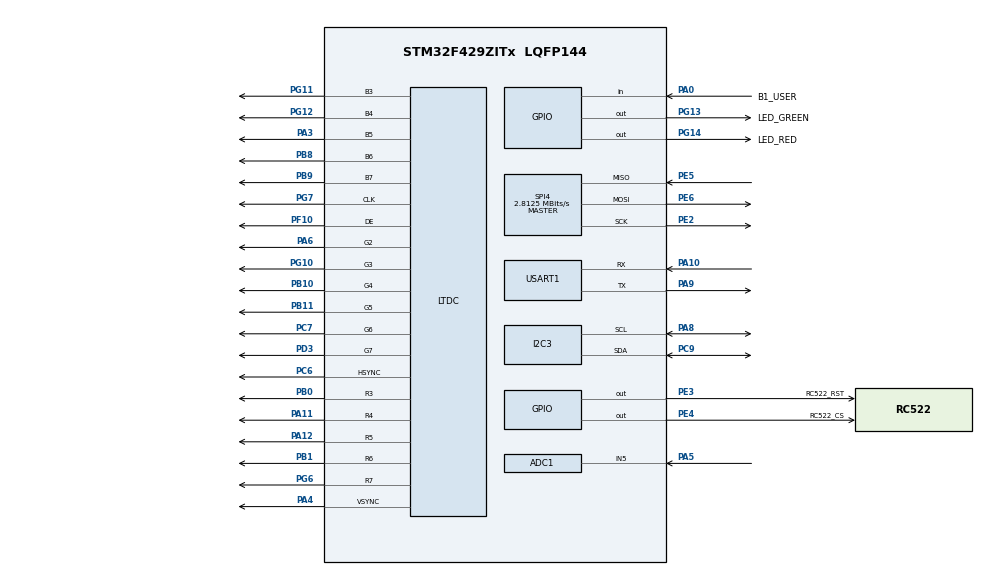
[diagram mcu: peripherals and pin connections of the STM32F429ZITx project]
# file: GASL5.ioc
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ADC1.Channel-0\#ChannelRegularConversion=ADC_CHANNEL_5
ADC1.ContinuousConvMode=ENABLE
ADC1.NbrOfConversionFlag=1
ADC1.Rank-0\#ChannelRegularConversion=1
ADC1.SamplingTime-0\#ChannelRegularConversion=ADC_SAMPLETIME_56CYCLES
ADC1.master=1
DMA2D.ColorMode=DMA2D_OUTPUT_RGB565
Dma.ADC1.0.Direction=DMA_PERIPH_TO_MEMORY
Dma.ADC1.0.FIFOMode=DMA_FIFOMODE_DISABLE
Dma.ADC1.0.Instance=DMA2_Stream0
Dma.ADC1.0.MemDataAlignment=DMA_MDATAALIGN_HALFWORD
Dma.ADC1.0.MemInc=DMA_MINC_ENABLE
Dma.ADC1.0.Mode=DMA_CIRCULAR
Dma.ADC1.0.PeriphDataAlignment=DMA_PDATAALIGN_HALFWORD
Dma.ADC1.0.PeriphInc=DMA_PINC_DISABLE
Dma.ADC1.0.Priority=DMA_PRIORITY_HIGH
Dma.Request0=ADC1
Dma.Request1=USART1_TX
Dma.USART1_TX.1.Direction=DMA_MEMORY_TO_PERIPH
Dma.USART1_TX.1.FIFOMode=DMA_FIFOMODE_DISABLE
Dma.USART1_TX.1.Instance=DMA2_Stream7
Dma.USART1_TX.1.MemDataAlignment=DMA_MDATAALIGN_BYTE
Dma.USART1_TX.1.MemInc=DMA_MINC_ENABLE
Dma.USART1_TX.1.Mode=DMA_NORMAL
Dma.USART1_TX.1.PeriphDataAlignment=DMA_PDATAALIGN_BYTE
Dma.USART1_TX.1.PeriphInc=DMA_PINC_DISABLE
Dma.USART1_TX.1.Priority=DMA_PRIORITY_LOW
LTDC.Alpha0_L0=0
LTDC.Alpha_L0=255
LTDC.BlendingFactor1_L0=LTDC_BLENDING_FACTOR1_PAxCA
LTDC.BlendingFactor2_L0=LTDC_BLENDING_FACTOR2_PAxCA
LTDC.ImageHeight_L0=320
LTDC.ImageWidth_L0=240
LTDC.Layers=0
LTDC.PixelFormat_L0=LTDC_PIXEL_FORMAT_RGB565
LTDC.WindowX1_L0=240
LTDC.WindowY1_L0=320
Mcu.Family=STM32F4
Mcu.Name=STM32F429ZITx
Mcu.Package=LQFP144
NVIC.DMA2_Stream0_IRQn=true\:0\:0\:false\:false\:true\:false\:true\:true
NVIC.DMA2_Stream7_IRQn=true\:0\:0\:false\:false\:true\:false\:true\:true
NVIC.PriorityGroup=NVIC_PRIORITYGROUP_4
NVIC.TIM6_DAC_IRQn=true\:15\:0\:false\:false\:true\:false\:true\:true
NVIC.TimeBase=TIM6_DAC_IRQn
NVIC.TimeBaseIP=TIM6
NVIC.USART1_IRQn=true\:0\:0\:false\:false\:true\:false\:true\:true
PA0/WKUP.GPIO_Label=B1_USER
PA0/WKUP.GPIO_PuPd=GPIO_PULLDOWN
PA0/WKUP.Signal=GPIO_Input
PA10.Mode=Asynchronous
PA10.Signal=USART1_RX
PA11.Mode=RGB565
PA11.Signal=LTDC_R4
PA12.Mode=RGB565
PA12.Signal=LTDC_R5
PA13.Mode=Serial_Wire
PA13.Signal=SYS_JTMS-SWDIO
PA14.Mode=Serial_Wire
PA14.Signal=SYS_JTCK-SWCLK
PA3.Mode=RGB565
PA3.Signal=LTDC_B5
PA4.Mode=RGB565
PA4.Signal=LTDC_VSYNC
PA5.Signal=ADCx_IN5
PA6.Mode=RGB565
PA6.Signal=LTDC_G2
PA8.Mode=I2C
PA8.Signal=I2C3_SCL
PA9.Mode=Asynchronous
PA9.Signal=USART1_TX
PB0.Mode=RGB565
PB0.Signal=LTDC_R3
PB1.Mode=RGB565
PB1.Signal=LTDC_R6
PB10.Mode=RGB565
PB10.Signal=LTDC_G4
PB11.Mode=RGB565
PB11.Signal=LTDC_G5
PB8.Mode=RGB565
PB8.Signal=LTDC_B6
PB9.Mode=RGB565
PB9.Signal=LTDC_B7
PC6.Mode=RGB565
PC6.Signal=LTDC_HSYNC
PC7.Mode=RGB565
PC7.Signal=LTDC_G6
PC9.Mode=I2C
PC9.Signal=I2C3_SDA
PD3.Mode=RGB565
PD3.Signal=LTDC_G7
PE2.Mode=Full_Duplex_Master
PE2.Signal=SPI4_SCK
PE3.GPIO_Label=RC522_RST
PE3.GPIO_PuPd=GPIO_NOPULL
PE3.GPIO_Speed=GPIO_SPEED_FREQ_HIGH
PE3.PinState=GPIO_PIN_SET
PE3.Signal=GPIO_Output
PE4.GPIO_Label=RC522_CS
PE4.PinState=GPIO_PIN_SET
PE4.Signal=GPIO_Output
PE5.Mode=Full_Duplex_Master
PE5.Signal=SPI4_MISO
PE6.Mode=Full_Duplex_Master
PE6.Signal=SPI4_MOSI
PF10.Mode=RGB565
PF10.Signal=LTDC_DE
PG13.GPIO_Label=LED_GREEN
PG13.Signal=GPIO_Output
PG14.GPIO_Label=LED_RED
PG14.Signal=GPIO_Output
PG10.Mode=RGB565
PG10.Signal=LTDC_G3
PG11.Mode=RGB565
PG11.Signal=LTDC_B3
PG12.Mode=RGB565
PG12.Signal=LTDC_B4
PG6.Mode=RGB565
PG6.Signal=LTDC_R7
PG7.Mode=RGB565
PG7.Signal=LTDC_CLK
PH0/OSC_IN.Mode=HSE-External-Oscillator
PH0/OSC_IN.Signal=RCC_OSC_IN
PH1/OSC_OUT.Mode=HSE-External-Oscillator
PH1/OSC_OUT.Signal=RCC_OSC_OUT
ProjectManager.HeapSize=0x200
ProjectManager.StackSize=0x400
ProjectManager.TargetToolchain=STM32CubeIDE
RCC.48MHZClocksFreq_Value=90000000
RCC.AHBFreq_Value=180000000
RCC.APB1CLKDivider=RCC_HCLK_DIV4
RCC.APB1Freq_Value=45000000
RCC.APB1TimFreq_Value=90000000
RCC.APB2CLKDivider=RCC_HCLK_DIV2
RCC.APB2Freq_Value=90000000
RCC.APB2TimFreq_Value=180000000
RCC.CortexFreq_Value=180000000
RCC.EnbaleCSS=true
RCC.HCLKFreq_Value=180000000
RCC.HSE_VALUE=25000000
RCC.HSI_VALUE=16000000
RCC.LSE_VALUE=32768
RCC.PLLM=25
RCC.PLLN=360
RCC.PLLSAIDivR=RCC_PLLSAIDIVR_8
RCC.PLLSAIN=192
RCC.PLLSAIR=4
RCC.PLLSourceVirtual=RCC_PLLSOURCE_HSE
RCC.PWREXT_OverDrive=PWREXT_OverDrive_ACTIVATED
RCC.PWR_Regulator_Voltage_Scale=PWR_REGULATOR_VOLTAGE_SCALE1
RCC.SYSCLKFreq_VALUE=180000000
RCC.SYSCLKSource=RCC_SYSCLKSOURCE_PLLCLK
RCC.VCOOutputFreq_Value=360000000
SH.ADCx_IN5.0=ADC1_IN5,IN5
SPI4.BaudRatePrescaler=SPI_BAUDRATEPRESCALER_32
SPI4.CalculateBaudRate=2.8125 MBits/s
SPI4.Direction=SPI_DIRECTION_2LINES
SPI4.Mode=SPI_MODE_MASTER
SPI4.VirtualType=VM_MASTER
STMicroelectronics.X-CUBE-TOUCHGFX.4.25.0.ApplicationCcGraphicsJjApplication=TouchGFXOoGenerator
STMicroelectronics.X-CUBE-TOUCHGFX.4.25.0.tgfx_custom_height=320
STMicroelectronics.X-CUBE-TOUCHGFX.4.25.0.tgfx_display_interface=disp_ltdc
STMicroelectronics.X-CUBE-TOUCHGFX.4.25.0_IsPackSelfContextualization=true
USART1.VirtualMode=VM_ASYNC
VP_CRC_VS_CRC.Mode=CRC_Activate
VP_DMA2D_VS_DMA2D.Mode=DMA2D_Activate
VP_STMicroelectronics.X-CUBE-TOUCHGFX_VS_GraphicsJjApplication_4.25.0.Mode=GraphicsJjApplication
VP_SYS_VS_tim6.Mode=TIM6
board=custom

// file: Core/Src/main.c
/* USER CODE BEGIN Header */
/**
 ******************************************************************************
 * @file           : main.c
 * @brief          : Main program body
 ******************************************************************************
 * @attention
 *
 * Copyright (c) 2026 STMicroelectronics.
 * All rights reserved.
 *
 * This software is licensed under terms that can be found in the LICENSE file
 * in the root directory of this software component.
 * If no LICENSE file comes with this software, it is provided AS-IS.
 *
 ******************************************************************************
 */
/* USER CODE END Header */
#include "main.h"
#include "app_touchgfx.h"
#include "app_backend.h"

/* USER CODE BEGIN Includes */
#include "i2c_scanner.h"
#include "lcd_ili9341.h"
/* USER CODE END Includes */

ADC_HandleTypeDef hadc1;
DMA_HandleTypeDef hdma_adc1;

CRC_HandleTypeDef hcrc;

DMA2D_HandleTypeDef hdma2d;

I2C_HandleTypeDef hi2c3;

LTDC_HandleTypeDef hltdc;

SPI_HandleTypeDef hspi4;

UART_HandleTypeDef huart1;
DMA_HandleTypeDef hdma_usart1_tx;

void SystemClock_Config(void);
static void MX_GPIO_Init(void);
static void MX_DMA_Init(void);
static void MX_ADC1_Init(void);
static void MX_CRC_Init(void);
static void MX_I2C3_Init(void);
static void MX_SPI4_Init(void);
static void MX_USART1_UART_Init(void);
static void MX_DMA2D_Init(void);
static void MX_LTDC_Init(void);

int main(void)
{

  /* MCU Configuration--------------------------------------------------------*/

  /* Reset of all peripherals, Initializes the Flash interface and the Systick. */
  HAL_Init();

  /* Configure the system clock */
  SystemClock_Config();

  /* Initialize all configured peripherals */
  MX_GPIO_Init();
  MX_DMA_Init();
  MX_ADC1_Init();
  MX_CRC_Init();
  MX_I2C3_Init();
  MX_SPI4_Init();
  MX_USART1_UART_Init();
  MX_DMA2D_Init();
  MX_LTDC_Init();
  MX_TouchGFX_Init();

  /* USER CODE BEGIN 2 */
  if (!LCD_ILI9341_Init())
  {
    const char lcd_error[] = "LCD ILI9341 INIT FAILED\r\n";
    HAL_UART_Transmit(&huart1,
                      (uint8_t *)lcd_error,
                      sizeof(lcd_error) - 1U,
                      100U);
    Error_Handler();
  }
  else
  {
    const char lcd_ok[] = "LCD ILI9341 INIT OK\r\n";
    HAL_UART_Transmit(&huart1,
                      (uint8_t *)lcd_ok,
                      sizeof(lcd_ok) - 1U,
                      100U);
  }
  I2C_Scanner_Run(&hi2c3, &huart1);
  /* USER CODE END 2 */

  AppBackend_Init();

  /* Infinite loop */
  while (1)
  {

    MX_TouchGFX_Process();
    /* USER CODE BEGIN 3 */
    /*
     * Backend phải chạy độc lập với nhịp render/VSYNC của TouchGFX.
     * Các hàm bên trong tự giới hạn chu kỳ bằng HAL_GetTick().
     */
    AppBackend_Tick(HAL_GetTick());
  }
  /* USER CODE END 3 */
}

void SystemClock_Config(void)
{
  RCC_OscInitTypeDef RCC_OscInitStruct = {0};
  RCC_ClkInitTypeDef RCC_ClkInitStruct = {0};

  /** Configure the main internal regulator output voltage
   */
  __HAL_RCC_PWR_CLK_ENABLE();
  __HAL_PWR_VOLTAGESCALING_CONFIG(PWR_REGULATOR_VOLTAGE_SCALE1);

  /** Initializes the RCC Oscillators according to the specified parameters
   * in the RCC_OscInitTypeDef structure.
   */
  RCC_OscInitStruct.OscillatorType = RCC_OSCILLATORTYPE_HSE;
  RCC_OscInitStruct.HSEState = RCC_HSE_ON;
  RCC_OscInitStruct.PLL.PLLState = RCC_PLL_ON;
  RCC_OscInitStruct.PLL.PLLSource = RCC_PLLSOURCE_HSE;
  RCC_OscInitStruct.PLL.PLLM = 8;
  RCC_OscInitStruct.PLL.PLLN = 360;
  RCC_OscInitStruct.PLL.PLLP = RCC_PLLP_DIV2;
  RCC_OscInitStruct.PLL.PLLQ = 4;
  if (HAL_RCC_OscConfig(&RCC_OscInitStruct) != HAL_OK)
  {
    Error_Handler();
  }

  /** Activate the Over-Drive mode
   */
  if (HAL_PWREx_EnableOverDrive() != HAL_OK)
  {
    Error_Handler();
  }

  /** Initializes the CPU, AHB and APB buses clocks
   */
  RCC_ClkInitStruct.ClockType = RCC_CLOCKTYPE_HCLK | RCC_CLOCKTYPE_SYSCLK | RCC_CLOCKTYPE_PCLK1 | RCC_CLOCKTYPE_PCLK2;
  RCC_ClkInitStruct.SYSCLKSource = RCC_SYSCLKSOURCE_PLLCLK;
  RCC_ClkInitStruct.AHBCLKDivider = RCC_SYSCLK_DIV1;
  RCC_ClkInitStruct.APB1CLKDivider = RCC_HCLK_DIV4;
  RCC_ClkInitStruct.APB2CLKDivider = RCC_HCLK_DIV2;

  if (HAL_RCC_ClockConfig(&RCC_ClkInitStruct, FLASH_LATENCY_5) != HAL_OK)
  {
    Error_Handler();
  }

  /** Enables the Clock Security System
   */
  HAL_RCC_EnableCSS();
}

static void MX_ADC1_Init(void)
{

  ADC_ChannelConfTypeDef sConfig = {0};

  /** Configure the global features of the ADC (Clock, Resolution, Data Alignment and number of conversion)
   */
  hadc1.Instance = ADC1;
  hadc1.Init.ClockPrescaler = ADC_CLOCK_SYNC_PCLK_DIV4;
  hadc1.Init.Resolution = ADC_RESOLUTION_12B;
  hadc1.Init.ScanConvMode = DISABLE;
  hadc1.Init.ContinuousConvMode = ENABLE;
  hadc1.Init.DiscontinuousConvMode = DISABLE;
  hadc1.Init.ExternalTrigConvEdge = ADC_EXTERNALTRIGCONVEDGE_NONE;
  hadc1.Init.ExternalTrigConv = ADC_SOFTWARE_START;
  hadc1.Init.DataAlign = ADC_DATAALIGN_RIGHT;
  hadc1.Init.NbrOfConversion = 1;
  hadc1.Init.DMAContinuousRequests = ENABLE;
  hadc1.Init.EOCSelection = ADC_EOC_SINGLE_CONV;
  if (HAL_ADC_Init(&hadc1) != HAL_OK)
  {
    Error_Handler();
  }

  /** Configure for the selected ADC regular channel its corresponding rank in the sequencer and its sample time.
   */
  sConfig.Channel = ADC_CHANNEL_5;
  sConfig.Rank = 1;
  sConfig.SamplingTime = ADC_SAMPLETIME_56CYCLES;
  if (HAL_ADC_ConfigChannel(&hadc1, &sConfig) != HAL_OK)
  {
    Error_Handler();
  }
}

static void MX_CRC_Init(void)
{

  hcrc.Instance = CRC;
  if (HAL_CRC_Init(&hcrc) != HAL_OK)
  {
    Error_Handler();
  }
}

static void MX_DMA2D_Init(void)
{

  hdma2d.Instance = DMA2D;
  hdma2d.Init.Mode = DMA2D_M2M;
  hdma2d.Init.ColorMode = DMA2D_OUTPUT_RGB565;
  hdma2d.Init.OutputOffset = 0;
  hdma2d.LayerCfg[1].InputOffset = 0;
  hdma2d.LayerCfg[1].InputColorMode = DMA2D_INPUT_RGB565;
  hdma2d.LayerCfg[1].AlphaMode = DMA2D_NO_MODIF_ALPHA;
  hdma2d.LayerCfg[1].InputAlpha = 0;
  if (HAL_DMA2D_Init(&hdma2d) != HAL_OK)
  {
    Error_Handler();
  }
  if (HAL_DMA2D_ConfigLayer(&hdma2d, 1) != HAL_OK)
  {
    Error_Handler();
  }
}

static void MX_I2C3_Init(void)
{

  hi2c3.Instance = I2C3;
  hi2c3.Init.ClockSpeed = 100000;
  hi2c3.Init.DutyCycle = I2C_DUTYCYCLE_2;
  hi2c3.Init.OwnAddress1 = 0;
  hi2c3.Init.AddressingMode = I2C_ADDRESSINGMODE_7BIT;
  hi2c3.Init.DualAddressMode = I2C_DUALADDRESS_DISABLE;
  hi2c3.Init.OwnAddress2 = 0;
  hi2c3.Init.GeneralCallMode = I2C_GENERALCALL_DISABLE;
  hi2c3.Init.NoStretchMode = I2C_NOSTRETCH_DISABLE;
  if (HAL_I2C_Init(&hi2c3) != HAL_OK)
  {
    Error_Handler();
  }

  /** Configure Analogue filter
   */
  if (HAL_I2CEx_ConfigAnalogFilter(&hi2c3, I2C_ANALOGFILTER_ENABLE) != HAL_OK)
  {
    Error_Handler();
  }

  /** Configure Digital filter
   */
  if (HAL_I2CEx_ConfigDigitalFilter(&hi2c3, 0) != HAL_OK)
  {
    Error_Handler();
  }
}

static void MX_LTDC_Init(void)
{

  LTDC_LayerCfgTypeDef pLayerCfg = {0};

  hltdc.Instance = LTDC;
  hltdc.Init.HSPolarity = LTDC_HSPOLARITY_AL;
  hltdc.Init.VSPolarity = LTDC_VSPOLARITY_AL;
  hltdc.Init.DEPolarity = LTDC_DEPOLARITY_AL;
  hltdc.Init.PCPolarity = LTDC_PCPOLARITY_IPC;
  hltdc.Init.HorizontalSync = 9;
  hltdc.Init.VerticalSync = 1;
  hltdc.Init.AccumulatedHBP = 29;
  hltdc.Init.AccumulatedVBP = 3;
  hltdc.Init.AccumulatedActiveW = 269;
  hltdc.Init.AccumulatedActiveH = 323;
  hltdc.Init.TotalWidth = 279;
  hltdc.Init.TotalHeigh = 327;
  hltdc.Init.Backcolor.Blue = 0;
  hltdc.Init.Backcolor.Green = 0;
  hltdc.Init.Backcolor.Red = 0;
  if (HAL_LTDC_Init(&hltdc) != HAL_OK)
  {
    Error_Handler();
  }
  pLayerCfg.WindowX0 = 0;
  pLayerCfg.WindowX1 = 240;
  pLayerCfg.WindowY0 = 0;
  pLayerCfg.WindowY1 = 320;
  pLayerCfg.PixelFormat = LTDC_PIXEL_FORMAT_RGB565;
  pLayerCfg.Alpha = 255;
  pLayerCfg.Alpha0 = 0;
  pLayerCfg.BlendingFactor1 = LTDC_BLENDING_FACTOR1_PAxCA;
  pLayerCfg.BlendingFactor2 = LTDC_BLENDING_FACTOR2_PAxCA;
  pLayerCfg.FBStartAdress = 0;
  pLayerCfg.ImageWidth = 240;
  pLayerCfg.ImageHeight = 320;
  pLayerCfg.Backcolor.Blue = 0;
  pLayerCfg.Backcolor.Green = 0;
  pLayerCfg.Backcolor.Red = 0;
  if (HAL_LTDC_ConfigLayer(&hltdc, &pLayerCfg, 0) != HAL_OK)
  {
    Error_Handler();
  }
}

static void MX_SPI4_Init(void)
{

  /* SPI4 parameter configuration*/
  hspi4.Instance = SPI4;
  hspi4.Init.Mode = SPI_MODE_MASTER;
  hspi4.Init.Direction = SPI_DIRECTION_2LINES;
  hspi4.Init.DataSize = SPI_DATASIZE_8BIT;
  hspi4.Init.CLKPolarity = SPI_POLARITY_LOW;
  hspi4.Init.CLKPhase = SPI_PHASE_1EDGE;
  hspi4.Init.NSS = SPI_NSS_SOFT;
  hspi4.Init.BaudRatePrescaler = SPI_BAUDRATEPRESCALER_32;
  hspi4.Init.FirstBit = SPI_FIRSTBIT_MSB;
  hspi4.Init.TIMode = SPI_TIMODE_DISABLE;
  hspi4.Init.CRCCalculation = SPI_CRCCALCULATION_DISABLE;
  hspi4.Init.CRCPolynomial = 10;
  if (HAL_SPI_Init(&hspi4) != HAL_OK)
  {
    Error_Handler();
  }
}

static void MX_USART1_UART_Init(void)
{

  huart1.Instance = USART1;
  huart1.Init.BaudRate = 115200;
  huart1.Init.WordLength = UART_WORDLENGTH_8B;
  huart1.Init.StopBits = UART_STOPBITS_1;
  huart1.Init.Parity = UART_PARITY_NONE;
  huart1.Init.Mode = UART_MODE_TX_RX;
  huart1.Init.HwFlowCtl = UART_HWCONTROL_NONE;
  huart1.Init.OverSampling = UART_OVERSAMPLING_16;
  if (HAL_UART_Init(&huart1) != HAL_OK)
  {
    Error_Handler();
  }
}

static void MX_DMA_Init(void)
{

  /* DMA controller clock enable */
  __HAL_RCC_DMA2_CLK_ENABLE();

  /* DMA interrupt init */
  /* DMA2_Stream0_IRQn interrupt configuration */
  HAL_NVIC_SetPriority(DMA2_Stream0_IRQn, 0, 0);
  HAL_NVIC_EnableIRQ(DMA2_Stream0_IRQn);
  /* DMA2_Stream7_IRQn interrupt configuration */
  HAL_NVIC_SetPriority(DMA2_Stream7_IRQn, 0, 0);
  HAL_NVIC_EnableIRQ(DMA2_Stream7_IRQn);
}

static void MX_GPIO_Init(void)
{
  GPIO_InitTypeDef GPIO_InitStruct = {0};

  /* GPIO Ports Clock Enable */
  __HAL_RCC_GPIOE_CLK_ENABLE();
  __HAL_RCC_GPIOF_CLK_ENABLE();
  __HAL_RCC_GPIOH_CLK_ENABLE();
  __HAL_RCC_GPIOA_CLK_ENABLE();
  __HAL_RCC_GPIOB_CLK_ENABLE();
  __HAL_RCC_GPIOD_CLK_ENABLE();
  __HAL_RCC_GPIOC_CLK_ENABLE();
  __HAL_RCC_GPIOG_CLK_ENABLE();

  /*Configure GPIO pin Output Level */
  HAL_GPIO_WritePin(GPIOE, RC522_RST_Pin | RC522_CS_Pin, GPIO_PIN_SET);

  /*Configure GPIO pin Output Level */
  HAL_GPIO_WritePin(GPIOG, LED_GREEN_Pin | LED_RED_Pin, GPIO_PIN_RESET);

  /*Configure GPIO pin : RC522_RST_Pin */
  GPIO_InitStruct.Pin = RC522_RST_Pin;
  GPIO_InitStruct.Mode = GPIO_MODE_OUTPUT_PP;
  GPIO_InitStruct.Pull = GPIO_NOPULL;
  GPIO_InitStruct.Speed = GPIO_SPEED_FREQ_HIGH;
  HAL_GPIO_Init(RC522_RST_GPIO_Port, &GPIO_InitStruct);

  /*Configure GPIO pin : RC522_CS_Pin */
  GPIO_InitStruct.Pin = RC522_CS_Pin;
  GPIO_InitStruct.Mode = GPIO_MODE_OUTPUT_PP;
  GPIO_InitStruct.Pull = GPIO_NOPULL;
  GPIO_InitStruct.Speed = GPIO_SPEED_FREQ_LOW;
  HAL_GPIO_Init(RC522_CS_GPIO_Port, &GPIO_InitStruct);

  /*Configure GPIO pin : B1_USER_Pin */
  GPIO_InitStruct.Pin = B1_USER_Pin;
  GPIO_InitStruct.Mode = GPIO_MODE_INPUT;
  GPIO_InitStruct.Pull = GPIO_PULLDOWN;
  HAL_GPIO_Init(B1_USER_GPIO_Port, &GPIO_InitStruct);

  /*Configure GPIO pins : LED_GREEN_Pin LED_RED_Pin */
  GPIO_InitStruct.Pin = LED_GREEN_Pin | LED_RED_Pin;
  GPIO_InitStruct.Mode = GPIO_MODE_OUTPUT_PP;
  GPIO_InitStruct.Pull = GPIO_NOPULL;
  GPIO_InitStruct.Speed = GPIO_SPEED_FREQ_LOW;
  HAL_GPIO_Init(GPIOG, &GPIO_InitStruct);

}

void HAL_TIM_PeriodElapsedCallback(TIM_HandleTypeDef *htim)
{
  if (htim->Instance == TIM6)
  {
    HAL_IncTick();
  }
}

void Error_Handler(void)
{
  __disable_irq();
  while (1)
  {
  }
}
